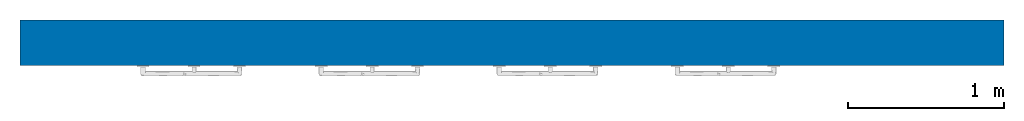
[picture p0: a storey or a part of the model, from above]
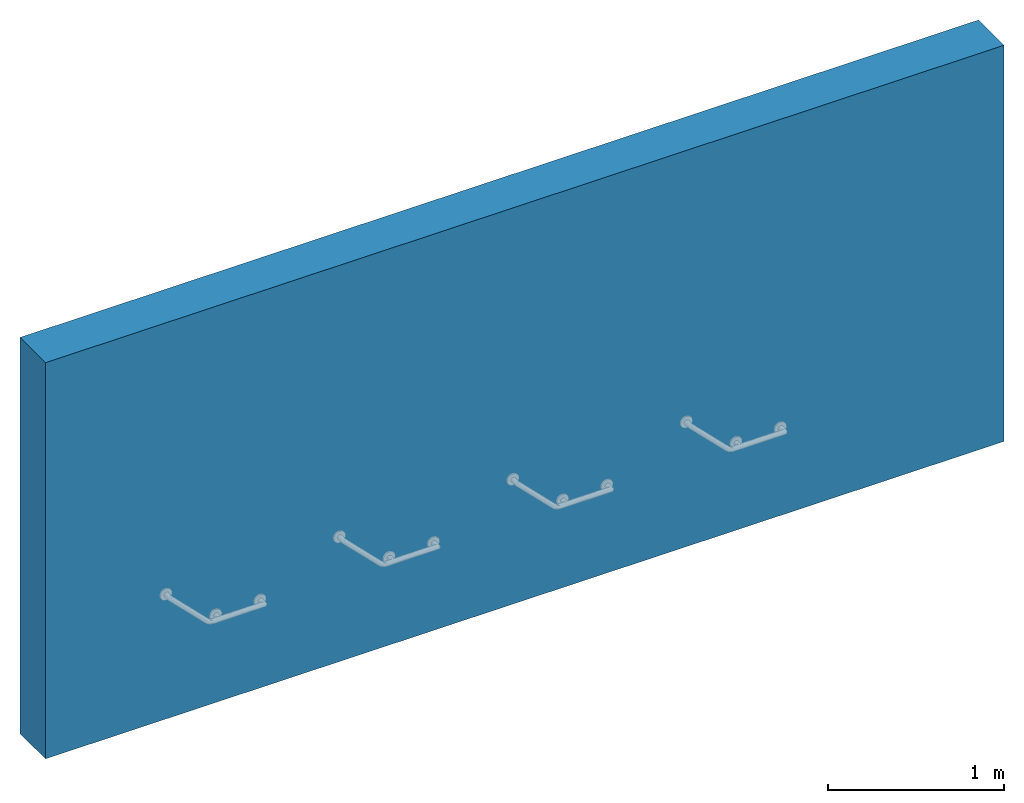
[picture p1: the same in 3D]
Properties of the parts of a building model (IFC2X3)

# File
Description: ViewDefinition [CoordinationView_V2.0]
File name: Project Number
Time: 2024-02-23T12:31:01
Written by: The EXPRESS Data Manager Version 5.02.0100.07 : 28 Aug 2013
Made in: 21.1.80.35 - Exporter 21.1.80.35 - Alternate UI 21.1.80.35
Comment: STEP Physical File produced by: The EXPRESS Data Manager Version 5.02.0100.07 : 28 Aug 2013 * Module: EDMstepFileFactory/EDMstandAlone * Creation date: Fri Feb 23 12:31:01 2024 * Host: DESKTOP-KN3O7NT * Database: C:\Users\SARAHS~1\AppData\Local\Temp\a389de1c-a770-4c6f-bffb-e4930adbdc5d\024b9f71-35f8-4710-8c02-d2a62bb9e4a5\ifc * Database version: 5507 * Database creation date: Fri Feb 23 12:30:55 2024 * Schema: IFC2X3 * Model: DataRepository.ifc * Model creation date: Fri Feb 23 12:30:56 2024 * Header model: DataRepository.ifc_HeaderModel * Header model creation date: Fri Feb 23 12:30:56 2024 * EDMuser: sdai-user * EDMgroup: sdai-group * License ID and type: 5605 : Permanent license. Expiry date: * EDMstepFileFactory options: 020000

# IfcProject, Project Number
LongName: Project Name; Phase: Project Status

# IfcSite, Default
RefLatitude: 51, 30, 23, 112487; RefLongitude: 0, -7, -37, -956022; RefElevation: 0 mm
Pset_ProductRequirements - Category: Project Information

# IfcBuilding
Pset_BuildingCommon - NumberOfStoreys: 1
Pset_ProductRequirements - Category: Project Information

# IfcBuildingStorey: Level:Circle Head - Project Datum, Level 0
LongName: Level 0; Elevation: 0 mm
Pset_AirSideSystemInformation - Name: Level 0
Pset_ProductRequirements - Name: Level 0; Category: Levels

# IfcBuildingElementProxy: Duten_SStHandrls_B615:Brushed Stainless Steel (4)
In: Level 0
Type - Classification: E2020200 Furniture & Accessories (Uniformat); Material: Duten_Metal_BrushedStainlessSteel
Type - Pset_BuildingElementProxyCommon - Reference: n/a
Type - Pset_ElementShading - Color: Defined by Finish
Type - Pset_ManufacturerOccurrence - BarCode: n/a; SerialNumber: n/a
Type - Pset_ManufacturerTypeInformation - ModelReference: Brushed Stainless Steel; Manufacturer: Duten
Type - Pset_PrecastConcreteElementGeneral - SerialNumber: n/a
Type - Pset_ProductRequirements - Name: StainlessSteelHandrails_B615_Duten; Category: Generic Models
Type - Pset_QuantityTakeOff - Reference: n/a
Type - Pset_ProvisionForVoid - Shape: Rectangle
Pset_BuildingElementProxyCommon - sets with these values: 2
Name (Duten_SStHandrls_B615:Brushed Stainless Steel:...)
314169
314210
314289
314296

# IfcWallStandardCase: Basic Wall:Wall-Ext_102Bwk-75Ins-100LBlk-12P, Basic Wall:Wall-Ext_102Bwk-75Ins-100LBlk-12P:314151
In: Level 0
Type - PredefinedType: STANDARD; Material: Brick, Common 102.5 mm, Fiberglass Batt 75 mm, Concrete Masonry Units _Low Density 100 mm, Plaster 12.5 mm
Type - Pset_ElementShading - Roughness: 914.4 mm
Type - Pset_ProductRequirements - Category: Walls
Type - Pset_QuantityTakeOff - Reference: Wall-Ext_102Bwk-75Ins-100LBlk-12P
Type - Pset_ReinforcementBarPitchOfWall - Reference: Wall-Ext_102Bwk-75Ins-100LBlk-12P
Type - Pset_WallCommon - Reference: Wall-Ext_102Bwk-75Ins-100LBlk-12P; ThermalTransmittance: 0.235926 kg/K/s3; IsExternal: no
Pset_QuantityTakeOff - sets with these values: 2
Pset_WallCommon - IsExternal: yes; ExtendToStructure: no; LoadBearing: no
